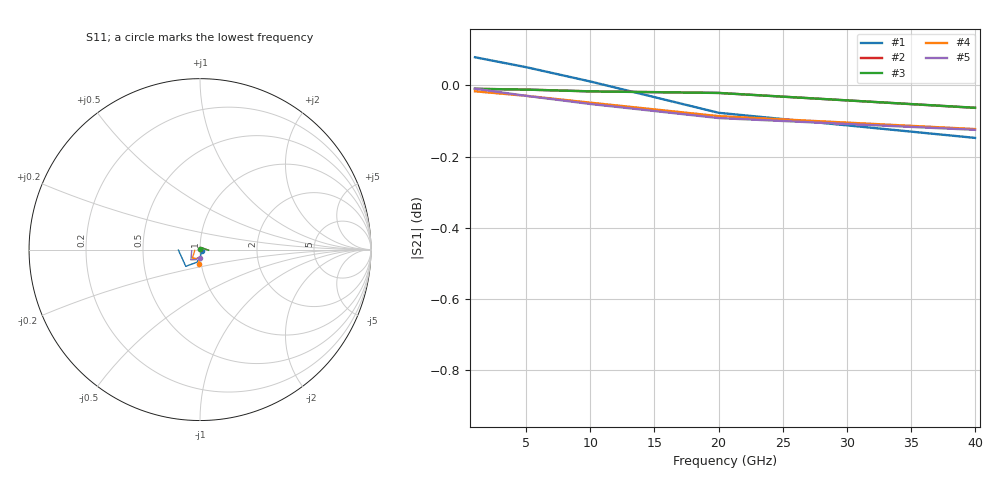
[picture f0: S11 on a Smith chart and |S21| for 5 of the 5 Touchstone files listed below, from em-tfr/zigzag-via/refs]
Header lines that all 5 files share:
! circuitRF-EM layout: thru/layout/thru.clay
! circuitRF-EM: re-running the EM setup rewrites this file. If circuitRF reports it as stale, the layout's cross-section changed after this file was written.
# GHz S RI R 50
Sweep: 1 GHz to 40 GHz
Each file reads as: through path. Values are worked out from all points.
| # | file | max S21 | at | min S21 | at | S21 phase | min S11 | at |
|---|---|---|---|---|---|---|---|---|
| 1 | e_thru.s2p | 0.08 dB | 1 GHz | -0.1 dB | 40 GHz | -24 deg at 10 GHz | -38.6 dB | 1 GHz |
| 2 | p_thru.s2p | -0.01 dB | 1 GHz | -0.1 dB | 40 GHz | -22 deg at 10 GHz | -57.5 dB | 1 GHz |
| 3 | p_thru_noband.s2p | -0.01 dB | 1 GHz | -0.1 dB | 40 GHz | -22 deg at 10 GHz | -57.6 dB | 1 GHz |
| 4 | pa_thru.s2p | -0.02 dB | 1 GHz | -0.1 dB | 40 GHz | -24 deg at 10 GHz | -30.1 dB | 40 GHz |
| 5 | pb_thru.s2p | -0.01 dB | 1 GHz | -0.1 dB | 40 GHz | -24 deg at 10 GHz | -26.2 dB | 40 GHz |
